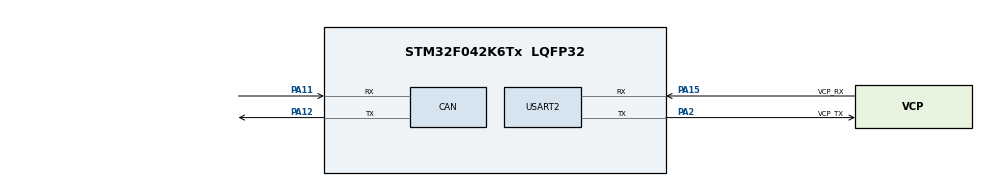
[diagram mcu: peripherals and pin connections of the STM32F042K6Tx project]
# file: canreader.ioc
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CAN.CalculateTimeBit=6000
CAN.CalculateTimeQuantum=2000.0
Mcu.Family=STM32F0
Mcu.Name=STM32F042K6Tx
Mcu.Package=LQFP32
PA11.Mode=Master
PA11.Signal=CAN_RX
PA12.Mode=Master
PA12.Signal=CAN_TX
PA13.GPIO_Label=SWDIO
PA13.Signal=SYS_SWDIO
PA14.GPIO_Label=SWCLK
PA14.Signal=SYS_SWCLK
PA15.GPIO_Label=VCP_RX
PA15.Mode=Asynchronous
PA15.Signal=USART2_RX
PA2.GPIO_Label=VCP_TX
PA2.Mode=Asynchronous
PA2.Signal=USART2_TX
PF0-OSC_IN.GPIO_Label=MCO
PF0-OSC_IN.Signal=RCC_OSC_IN
ProjectManager.HeapSize=0x200
ProjectManager.StackSize=0x400
ProjectManager.TargetToolchain=SW4STM32
USART2.VirtualMode-Asynchronous=VM_ASYNC
board=NUCLEO-F042K6

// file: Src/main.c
/**
  ******************************************************************************
  * File Name          : main.c
  * Description        : Main program body
  ******************************************************************************
  ** This notice applies to any and all portions of this file
  * that are not between comment pairs USER CODE BEGIN and
  * USER CODE END. Other portions of this file, whether
  * inserted by the user or by software development tools
  * are owned by their respective copyright owners.
  *
  * COPYRIGHT(c) 2017 STMicroelectronics
  *
  * Redistribution and use in source and binary forms, with or without modification,
  * are permitted provided that the following conditions are met:
  *   1. Redistributions of source code must retain the above copyright notice,
  *      this list of conditions and the following disclaimer.
  *   2. Redistributions in binary form must reproduce the above copyright notice,
  *      this list of conditions and the following disclaimer in the documentation
  *      and/or other materials provided with the distribution.
  *   3. Neither the name of STMicroelectronics nor the names of its contributors
  *      may be used to endorse or promote products derived from this software
  *      without specific prior written permission.
  *
  * THIS SOFTWARE IS PROVIDED BY THE COPYRIGHT HOLDERS AND CONTRIBUTORS "AS IS"
  * AND ANY EXPRESS OR IMPLIED WARRANTIES, INCLUDING, BUT NOT LIMITED TO, THE
  * IMPLIED WARRANTIES OF MERCHANTABILITY AND FITNESS FOR A PARTICULAR PURPOSE ARE
  * DISCLAIMED. IN NO EVENT SHALL THE COPYRIGHT HOLDER OR CONTRIBUTORS BE LIABLE
  * FOR ANY DIRECT, INDIRECT, INCIDENTAL, SPECIAL, EXEMPLARY, OR CONSEQUENTIAL
  * DAMAGES (INCLUDING, BUT NOT LIMITED TO, PROCUREMENT OF SUBSTITUTE GOODS OR
  * SERVICES; LOSS OF USE, DATA, OR PROFITS; OR BUSINESS INTERRUPTION) HOWEVER
  * CAUSED AND ON ANY THEORY OF LIABILITY, WHETHER IN CONTRACT, STRICT LIABILITY,
  * OR TORT (INCLUDING NEGLIGENCE OR OTHERWISE) ARISING IN ANY WAY OUT OF THE USE
  * OF THIS SOFTWARE, EVEN IF ADVISED OF THE POSSIBILITY OF SUCH DAMAGE.
  *
  ******************************************************************************
  */
#include <stdio.h>
#include <stdlib.h>
#include <string.h>
#include "stm32f0xx_hal.h"
#include "stm32f0xx_nucleo_32.h"
#include "main.h"
#include "app.h"

CAN_HandleTypeDef hcan;
UART_HandleTypeDef huart2;

/* USER CODE BEGIN PV */
/* Private definitions -------------------------------------------------------*/
/* Private variables ---------------------------------------------------------*/
/* Welcome Message */
uint8_t WelcomeMessage[] = "Trixlog CanReader Application\n";
/* CAN Messages */
CanTxMsgTypeDef	CAN_TxMessage;
CanRxMsgTypeDef CAN_RxMessage;
CanRxMsgTypeDef CAN_Rx1Message;

/* USER CODE END PV */

void SystemClock_Config(void);
static void MX_GPIO_Init(void);
static void MX_CAN_Init(void);
static void MX_USART2_UART_Init(void);

/* USER CODE BEGIN PFP */
/* Private function prototypes -----------------------------------------------*/

/* USER CODE END PFP */

int main(void)
{

  /* MCU Configuration----------------------------------------------------------*/

  /* Reset of all peripherals, Initializes the Flash interface and the Systick. */
  HAL_Init();

  /* Configure the system clock */
  SystemClock_Config();

  /* USER CODE BEGIN SysInit */
  /* Configure LED3 */
  BSP_LED_Init(LED3);
  /* USER CODE END SysInit */

  /* Initialize all configured peripherals */
  MX_GPIO_Init();
  MX_CAN_Init();
  MX_USART2_UART_Init();

  /* USER CODE BEGIN 2 */
  AppInit();
  HAL_UART_Transmit(&huart2,WelcomeMessage, sizeof(WelcomeMessage), 5000);
  /* USER CODE END 2 */

  /* Infinite loop */
  while (1)
  {
	  if( HAL_CAN_Receive(&hcan, CAN_FIFO0,1000) == HAL_OK )
	  {
		  AppStateMachineHandler(hcan.pRxMsg);
	  }
	  BSP_LED_Toggle(LED3);
	  HAL_Delay(100);
  }

}

/** System Clock Configuration
*/
void SystemClock_Config(void)
{
	  RCC_ClkInitTypeDef RCC_ClkInitStruct;
	  RCC_OscInitTypeDef RCC_OscInitStruct;

	  /* No HSE Oscillator on Nucleo, Activate PLL with HSI as source */
	  RCC_OscInitStruct.OscillatorType = RCC_OSCILLATORTYPE_NONE;
	  RCC_OscInitStruct.PLL.PLLState = RCC_PLL_ON;
	  RCC_OscInitStruct.PLL.PLLSource = RCC_PLLSOURCE_HSI;
	  RCC_OscInitStruct.PLL.PREDIV = RCC_PREDIV_DIV1;
	  RCC_OscInitStruct.PLL.PLLMUL = RCC_PLL_MUL6;
	  if (HAL_RCC_OscConfig(&RCC_OscInitStruct)!= HAL_OK)
	  {
	    /* Initialization Error */
	    while(1);
	  }

	  /* Select PLL as system clock source and configure the HCLK, PCLK1 clocks dividers */
	  RCC_ClkInitStruct.ClockType = (RCC_CLOCKTYPE_SYSCLK | RCC_CLOCKTYPE_HCLK | RCC_CLOCKTYPE_PCLK1);
	  RCC_ClkInitStruct.SYSCLKSource = RCC_SYSCLKSOURCE_PLLCLK;
	  RCC_ClkInitStruct.AHBCLKDivider = RCC_SYSCLK_DIV1;
	  RCC_ClkInitStruct.APB1CLKDivider = RCC_HCLK_DIV1;
	  if (HAL_RCC_ClockConfig(&RCC_ClkInitStruct, FLASH_LATENCY_1)!= HAL_OK)
	  {
	    /* Initialization Error */
	    while(1);
	  }
}

/* CAN init function */
static void MX_CAN_Init(void)
{
  CAN_FilterConfTypeDef  sFilterConfig;

  hcan.Instance = CAN;
  hcan.pTxMsg = &CAN_TxMessage;
  hcan.pRxMsg = &CAN_RxMessage;
  hcan.pRx1Msg = &CAN_Rx1Message;

  hcan.Init.TTCM = DISABLE;
  hcan.Init.ABOM = DISABLE;
  hcan.Init.AWUM = DISABLE;
  hcan.Init.NART = DISABLE;
  hcan.Init.RFLM = DISABLE;
  hcan.Init.TXFP = DISABLE;

  hcan.Init.Mode = CAN_MODE_NORMAL;

  hcan.Init.SJW = CAN_SJW_1TQ;
  hcan.Init.BS1 = CAN_BS1_5TQ;
  hcan.Init.BS2 = CAN_BS2_6TQ;
  hcan.Init.Prescaler = 16;

  if (HAL_CAN_Init(&hcan) != HAL_OK)
  {
    _Error_Handler(__FILE__, __LINE__);
  }

  /*##-2- Configure the CAN Filter ###########################################*/
  sFilterConfig.FilterNumber = 0;
  sFilterConfig.FilterMode = CAN_FILTERMODE_IDMASK;
  sFilterConfig.FilterScale = CAN_FILTERSCALE_32BIT;
  sFilterConfig.FilterIdHigh = 0x0000;
  sFilterConfig.FilterIdLow = 0x0000;
  sFilterConfig.FilterMaskIdHigh = 0x0000;
  sFilterConfig.FilterMaskIdLow = 0x0000;
  sFilterConfig.FilterFIFOAssignment = CAN_FILTER_FIFO0;
  sFilterConfig.FilterActivation = ENABLE;
  sFilterConfig.BankNumber = 0;

  if (HAL_CAN_ConfigFilter(&hcan, &sFilterConfig) != HAL_OK)
  {
    /* Filter configuration Error */
    Error_Handler();
  }

}

/* USART2 init function */
static void MX_USART2_UART_Init(void)
{

  huart2.Instance = USART2;
  huart2.Init.BaudRate = 115200;
  huart2.Init.StopBits = UART_STOPBITS_1;
  huart2.Init.Parity = UART_PARITY_NONE;
  huart2.Init.Mode = UART_MODE_TX_RX;
  huart2.Init.HwFlowCtl = UART_HWCONTROL_NONE;
  huart2.Init.WordLength   = UART_WORDLENGTH_8B;
  if (HAL_UART_Init(&huart2) != HAL_OK)
  {
    _Error_Handler(__FILE__, __LINE__);
  }

}

/** Configure pins as
        * Analog
        * Input
        * Output
        * EVENT_OUT
        * EXTI
*/
static void MX_GPIO_Init(void)
{

  /* GPIO Ports Clock Enable */
  __HAL_RCC_GPIOF_CLK_ENABLE();
  __HAL_RCC_GPIOA_CLK_ENABLE();

}

void _Error_Handler(char * file, int line)
{
  while(1)
  {
  }
}

/************************ (C) COPYRIGHT STMicroelectronics *****END OF FILE****/
